One B-rep face of a CAD part: STEP entity #596.
In plain terms, the planar face has unit normal (0, 0, -1).
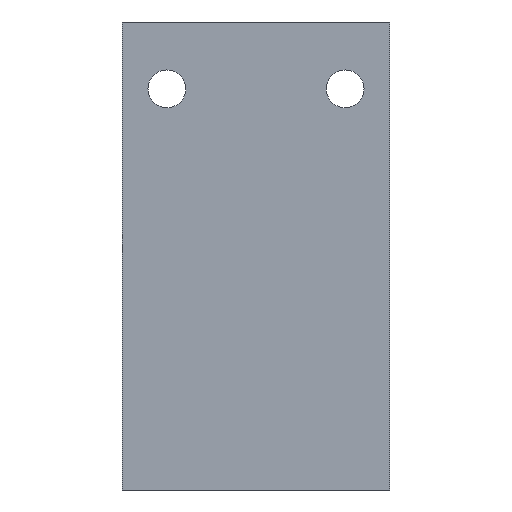
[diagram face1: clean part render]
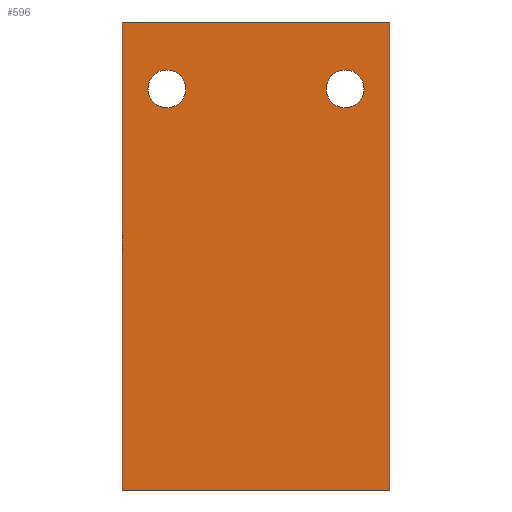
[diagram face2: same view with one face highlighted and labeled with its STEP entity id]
Its self-contained STEP definition (entity closure, numbers rounded to 3 decimals):
#40 = VERTEX_POINT('',#41);
#41 = CARTESIAN_POINT('',(4.,50.,56.));
#50 = PLANE('',#51);
#51 = AXIS2_PLACEMENT_3D('',#52,#53,#54);
#52 = CARTESIAN_POINT('',(4.,50.,56.));
#53 = DIRECTION('',(1.,0.,-0.));
#54 = DIRECTION('',(0.,0.,1.));
#62 = PLANE('',#63);
#63 = AXIS2_PLACEMENT_3D('',#64,#65,#66);
#64 = CARTESIAN_POINT('',(4.,50.,56.));
#65 = DIRECTION('',(-0.,1.,0.));
#66 = DIRECTION('',(0.,0.,1.));
#74 = EDGE_CURVE('',#40,#75,#77,.T.);
#75 = VERTEX_POINT('',#76);
#76 = CARTESIAN_POINT('',(4.,92.,56.));
#77 = SURFACE_CURVE('',#78,(#82,#89),.PCURVE_S1.);
#78 = LINE('',#79,#80);
#79 = CARTESIAN_POINT('',(4.,50.,56.));
#80 = VECTOR('',#81,1.);
#81 = DIRECTION('',(-0.,1.,0.));
#82 = PCURVE('',#50,#83);
#83 = DEFINITIONAL_REPRESENTATION('',(#84),#88);
#84 = LINE('',#85,#86);
#85 = CARTESIAN_POINT('',(0.,0.));
#86 = VECTOR('',#87,1.);
#87 = DIRECTION('',(0.,-1.));
#88 = ( GEOMETRIC_REPRESENTATION_CONTEXT(2) 
PARAMETRIC_REPRESENTATION_CONTEXT() REPRESENTATION_CONTEXT('2D SPACE',''
  ) );
#89 = PCURVE('',#90,#95);
#90 = PLANE('',#91);
#91 = AXIS2_PLACEMENT_3D('',#92,#93,#94);
#92 = CARTESIAN_POINT('',(4.,50.,56.));
#93 = DIRECTION('',(0.,0.,1.));
#94 = DIRECTION('',(1.,0.,-0.));
#95 = DEFINITIONAL_REPRESENTATION('',(#96),#100);
#96 = LINE('',#97,#98);
#97 = CARTESIAN_POINT('',(0.,0.));
#98 = VECTOR('',#99,1.);
#99 = DIRECTION('',(0.,1.));
#100 = ( GEOMETRIC_REPRESENTATION_CONTEXT(2) 
PARAMETRIC_REPRESENTATION_CONTEXT() REPRESENTATION_CONTEXT('2D SPACE',''
  ) );
#118 = PLANE('',#119);
#119 = AXIS2_PLACEMENT_3D('',#120,#121,#122);
#120 = CARTESIAN_POINT('',(4.,92.,56.));
#121 = DIRECTION('',(-0.,1.,0.));
#122 = DIRECTION('',(0.,0.,1.));
#159 = EDGE_CURVE('',#40,#160,#162,.T.);
#160 = VERTEX_POINT('',#161);
#161 = CARTESIAN_POINT('',(28.,50.,56.));
#162 = SURFACE_CURVE('',#163,(#167,#174),.PCURVE_S1.);
#163 = LINE('',#164,#165);
#164 = CARTESIAN_POINT('',(4.,50.,56.));
#165 = VECTOR('',#166,1.);
#166 = DIRECTION('',(1.,0.,-0.));
#167 = PCURVE('',#62,#168);
#168 = DEFINITIONAL_REPRESENTATION('',(#169),#173);
#169 = LINE('',#170,#171);
#170 = CARTESIAN_POINT('',(0.,0.));
#171 = VECTOR('',#172,1.);
#172 = DIRECTION('',(0.,1.));
#173 = ( GEOMETRIC_REPRESENTATION_CONTEXT(2) 
PARAMETRIC_REPRESENTATION_CONTEXT() REPRESENTATION_CONTEXT('2D SPACE',''
  ) );
#174 = PCURVE('',#90,#175);
#175 = DEFINITIONAL_REPRESENTATION('',(#176),#180);
#176 = LINE('',#177,#178);
#177 = CARTESIAN_POINT('',(0.,0.));
#178 = VECTOR('',#179,1.);
#179 = DIRECTION('',(1.,0.));
#180 = ( GEOMETRIC_REPRESENTATION_CONTEXT(2) 
PARAMETRIC_REPRESENTATION_CONTEXT() REPRESENTATION_CONTEXT('2D SPACE',''
  ) );
#220 = PLANE('',#221);
#221 = AXIS2_PLACEMENT_3D('',#222,#223,#224);
#222 = CARTESIAN_POINT('',(28.,50.,56.));
#223 = DIRECTION('',(1.,0.,-0.));
#224 = DIRECTION('',(0.,0.,1.));
#401 = CYLINDRICAL_SURFACE('',#402,1.7);
#402 = AXIS2_PLACEMENT_3D('',#403,#404,#405);
#403 = CARTESIAN_POINT('',(8.,56.,54.));
#404 = DIRECTION('',(0.,0.,1.));
#405 = DIRECTION('',(1.,0.,-0.));
#432 = CYLINDRICAL_SURFACE('',#433,1.7);
#433 = AXIS2_PLACEMENT_3D('',#434,#435,#436);
#434 = CARTESIAN_POINT('',(24.,56.,54.));
#435 = DIRECTION('',(0.,0.,1.));
#436 = DIRECTION('',(1.,0.,-0.));
#523 = VERTEX_POINT('',#524);
#524 = CARTESIAN_POINT('',(28.,92.,56.));
#545 = EDGE_CURVE('',#523,#75,#546,.T.);
#546 = SURFACE_CURVE('',#547,(#551,#558),.PCURVE_S1.);
#547 = LINE('',#548,#549);
#548 = CARTESIAN_POINT('',(28.,92.,56.));
#549 = VECTOR('',#550,1.);
#550 = DIRECTION('',(-1.,0.,0.));
#551 = PCURVE('',#118,#552);
#552 = DEFINITIONAL_REPRESENTATION('',(#553),#557);
#553 = LINE('',#554,#555);
#554 = CARTESIAN_POINT('',(0.,24.));
#555 = VECTOR('',#556,1.);
#556 = DIRECTION('',(0.,-1.));
#557 = ( GEOMETRIC_REPRESENTATION_CONTEXT(2) 
PARAMETRIC_REPRESENTATION_CONTEXT() REPRESENTATION_CONTEXT('2D SPACE',''
  ) );
#558 = PCURVE('',#90,#559);
#559 = DEFINITIONAL_REPRESENTATION('',(#560),#564);
#560 = LINE('',#561,#562);
#561 = CARTESIAN_POINT('',(24.,42.));
#562 = VECTOR('',#563,1.);
#563 = DIRECTION('',(-1.,0.));
#564 = ( GEOMETRIC_REPRESENTATION_CONTEXT(2) 
PARAMETRIC_REPRESENTATION_CONTEXT() REPRESENTATION_CONTEXT('2D SPACE',''
  ) );
#596 = ADVANCED_FACE('',(#597,#623,#649),#90,.F.);
#597 = FACE_BOUND('',#598,.F.);
#598 = EDGE_LOOP('',(#599,#600,#601,#622));
#599 = ORIENTED_EDGE('',*,*,#74,.F.);
#600 = ORIENTED_EDGE('',*,*,#159,.T.);
#601 = ORIENTED_EDGE('',*,*,#602,.T.);
#602 = EDGE_CURVE('',#160,#523,#603,.T.);
#603 = SURFACE_CURVE('',#604,(#608,#615),.PCURVE_S1.);
#604 = LINE('',#605,#606);
#605 = CARTESIAN_POINT('',(28.,50.,56.));
#606 = VECTOR('',#607,1.);
#607 = DIRECTION('',(-0.,1.,0.));
#608 = PCURVE('',#90,#609);
#609 = DEFINITIONAL_REPRESENTATION('',(#610),#614);
#610 = LINE('',#611,#612);
#611 = CARTESIAN_POINT('',(24.,0.));
#612 = VECTOR('',#613,1.);
#613 = DIRECTION('',(0.,1.));
#614 = ( GEOMETRIC_REPRESENTATION_CONTEXT(2) 
PARAMETRIC_REPRESENTATION_CONTEXT() REPRESENTATION_CONTEXT('2D SPACE',''
  ) );
#615 = PCURVE('',#220,#616);
#616 = DEFINITIONAL_REPRESENTATION('',(#617),#621);
#617 = LINE('',#618,#619);
#618 = CARTESIAN_POINT('',(0.,0.));
#619 = VECTOR('',#620,1.);
#620 = DIRECTION('',(0.,-1.));
#621 = ( GEOMETRIC_REPRESENTATION_CONTEXT(2) 
PARAMETRIC_REPRESENTATION_CONTEXT() REPRESENTATION_CONTEXT('2D SPACE',''
  ) );
#622 = ORIENTED_EDGE('',*,*,#545,.T.);
#623 = FACE_BOUND('',#624,.F.);
#624 = EDGE_LOOP('',(#625));
#625 = ORIENTED_EDGE('',*,*,#626,.F.);
#626 = EDGE_CURVE('',#627,#627,#629,.T.);
#627 = VERTEX_POINT('',#628);
#628 = CARTESIAN_POINT('',(9.7,56.,56.));
#629 = SURFACE_CURVE('',#630,(#635,#642),.PCURVE_S1.);
#630 = CIRCLE('',#631,1.7);
#631 = AXIS2_PLACEMENT_3D('',#632,#633,#634);
#632 = CARTESIAN_POINT('',(8.,56.,56.));
#633 = DIRECTION('',(0.,0.,1.));
#634 = DIRECTION('',(1.,0.,-0.));
#635 = PCURVE('',#90,#636);
#636 = DEFINITIONAL_REPRESENTATION('',(#637),#641);
#637 = CIRCLE('',#638,1.7);
#638 = AXIS2_PLACEMENT_2D('',#639,#640);
#639 = CARTESIAN_POINT('',(4.,6.));
#640 = DIRECTION('',(1.,0.));
#641 = ( GEOMETRIC_REPRESENTATION_CONTEXT(2) 
PARAMETRIC_REPRESENTATION_CONTEXT() REPRESENTATION_CONTEXT('2D SPACE',''
  ) );
#642 = PCURVE('',#401,#643);
#643 = DEFINITIONAL_REPRESENTATION('',(#644),#648);
#644 = LINE('',#645,#646);
#645 = CARTESIAN_POINT('',(0.,2.));
#646 = VECTOR('',#647,1.);
#647 = DIRECTION('',(1.,0.));
#648 = ( GEOMETRIC_REPRESENTATION_CONTEXT(2) 
PARAMETRIC_REPRESENTATION_CONTEXT() REPRESENTATION_CONTEXT('2D SPACE',''
  ) );
#649 = FACE_BOUND('',#650,.F.);
#650 = EDGE_LOOP('',(#651));
#651 = ORIENTED_EDGE('',*,*,#652,.F.);
#652 = EDGE_CURVE('',#653,#653,#655,.T.);
#653 = VERTEX_POINT('',#654);
#654 = CARTESIAN_POINT('',(25.7,56.,56.));
#655 = SURFACE_CURVE('',#656,(#661,#668),.PCURVE_S1.);
#656 = CIRCLE('',#657,1.7);
#657 = AXIS2_PLACEMENT_3D('',#658,#659,#660);
#658 = CARTESIAN_POINT('',(24.,56.,56.));
#659 = DIRECTION('',(0.,0.,1.));
#660 = DIRECTION('',(1.,0.,-0.));
#661 = PCURVE('',#90,#662);
#662 = DEFINITIONAL_REPRESENTATION('',(#663),#667);
#663 = CIRCLE('',#664,1.7);
#664 = AXIS2_PLACEMENT_2D('',#665,#666);
#665 = CARTESIAN_POINT('',(20.,6.));
#666 = DIRECTION('',(1.,0.));
#667 = ( GEOMETRIC_REPRESENTATION_CONTEXT(2) 
PARAMETRIC_REPRESENTATION_CONTEXT() REPRESENTATION_CONTEXT('2D SPACE',''
  ) );
#668 = PCURVE('',#432,#669);
#669 = DEFINITIONAL_REPRESENTATION('',(#670),#674);
#670 = LINE('',#671,#672);
#671 = CARTESIAN_POINT('',(0.,2.));
#672 = VECTOR('',#673,1.);
#673 = DIRECTION('',(1.,0.));
#674 = ( GEOMETRIC_REPRESENTATION_CONTEXT(2) 
PARAMETRIC_REPRESENTATION_CONTEXT() REPRESENTATION_CONTEXT('2D SPACE',''
  ) );
